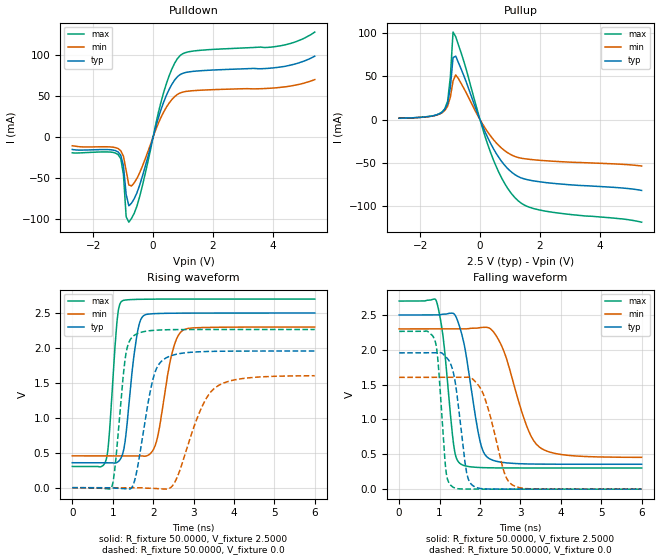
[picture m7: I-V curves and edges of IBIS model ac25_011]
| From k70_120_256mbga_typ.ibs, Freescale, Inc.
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|   Model ac25_011
[Model]  ac25_011
Model_type Output
Polarity   Non-Inverting
Enable   Active-High
Vmeas =  1.2500V
Cref =   5.0000pF
Rref =   50.0000
C_comp   2.8000pF   2.5000pF   3.3000pF
[Temperature Range]   25.0000   0.1250k   -40.0000
[Voltage Range]   2.5000V   2.3000V   2.7000V
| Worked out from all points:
|   slope of the pulldown table from 0 to 0.375 V, typ, clamps not added: 8.44 ohm
|   slope of the pullup table from 0 to 0.375 V, typ, clamps not added: 13 ohm
|   rising waveform, R_fixture 50.0000, V_fixture 2.5000: 20-80 % time 237ps typ, 326ps min, 165ps max; typ from 0.357 V to 2.5 V
|   rising waveform, R_fixture 50.0000, V_fixture 0.0: 20-80 % time 357ps typ, 618ps min, 215ps max; typ from 0 V to 1.96 V
|   falling waveform, R_fixture 50.0000, V_fixture 2.5000: 20-80 % time 355ps typ, 590ps min, 239ps max; typ from 2.5 V to 0.357 V
|   falling waveform, R_fixture 50.0000, V_fixture 0.0: 20-80 % time 250ps typ, 427ps min, 163ps max; typ from 1.96 V to 0 V
[Pulldown]
|Voltage   I(typ)   I(min)   I(max)
-2.7V     -15.15mA   -10.66mA   -19.23mA
-1.17V    -18.15mA   -14.03mA   -21.31mA
-1.08V    -22.21mA   -16.65mA   -26.35mA
-990mV    -35.19mA   -23.45mA   -45.8mA
-900mV    -69.89mA   -40.79mA   -97.1mA
-810mV    -83.68mA   -58.36mA   -103.6mA
-450mV    -58.66mA   -43.64mA   -72.6mA
360mV     43.1mA     30.89mA    55.11mA
630mV     64.28mA    45.66mA    82.94mA
900mV     75.87mA    53.52mA    98.99mA
4.23V     85.03mA    60.3mA     110.8mA
5.4V      98.3mA     69.8mA     127.6mA
[Pullup]
|Voltage   I(typ)   I(min)   I(max)
-2.7V     1.5mA      1.5mA      1.5mA
-1.17V    11.9mA     10.58mA    12.73mA
-1.08V    18.75mA    15.51mA    21.24mA
-990mV    36.75mA    25.9mA     48.78mA
-900mV    71.45mA    44.56mA    100.8mA
-810mV    73.08mA    51.48mA    95.46mA
-720mV    65.66mA    47.17mA    86.05mA
360mV     -27.87mA   -19.2mA    -38.53mA
720mV     -48.12mA   -32.86mA   -67.1mA
1.17V     -63.57mA   -42.6mA    -90.11mA
2.16V     -72.48mA   -47.39mA   -105.4mA
5.4V      -81.68mA   -53.55mA   -118.3mA
[Ramp]
| variable   typ   min   max
dV/dt_r  1.1737/0.3567n   0.9617/0.6175n   1.3589/0.2153n
dV/dt_f  1.2856/0.3546n   1.1061/0.5897n   1.4377/0.2388n
R_load = 50.0000
[Rising Waveform]
R_fixture= 50.0000
V_fixture= 2.5000
V_fixture_min= 2.3000
V_fixture_max= 2.7000
|time   V(typ)   V(min)   V(max)
0s        357.4mV    455.5mV    303.8mV
832.9ps   357.4mV    455.5mV    390.9mV
1.113ns   363.8mV    455.5mV    2.416V
1.225ns   448.8mV    455.5mV    2.67V
1.582ns   2.119V     455.5mV    2.696V
1.758ns   2.459V     452.2mV    2.698V
2.066ns   2.492V     627.4mV    2.699V
2.434ns   2.497V     1.841V     2.7V
2.706ns   2.499V     2.24V      2.7V
6ns       2.5V       2.3V       2.7V
[Rising Waveform]
R_fixture= 50.0000
V_fixture= 0.0
|time   V(typ)   V(min)   V(max)
0s        2.817nV    276.3nV    859.2pV
975.6ps   376.2uV    286.5nV    8.971mV
1.068ns   -7.425mV   262nV      350.9mV
1.315ns   -17.38mV   506.8nV    1.872V
1.561ns   143mV      -11.37uV   2.191V
1.987ns   1.532V     -8.683mV   2.251V
2.277ns   1.843V     -19.25mV   2.26V
2.566ns   1.909V     111.1mV    2.263V
3.512ns   1.952V     1.42V      2.265V
6ns       1.956V     1.603V     2.265V
[Falling Waveform]
R_fixture= 50.0000
V_fixture= 2.5000
V_fixture_min= 2.3000
V_fixture_max= 2.7000
|time   V(typ)   V(min)   V(max)
0s        2.5V       2.3V       2.7V
920.6ps   2.5V       2.3V       2.7V
1.098ns   2.512V     2.3V       2.135V
1.365ns   2.512V     2.3V       571.5mV
1.526ns   2.276V     2.3V       360mV
1.976ns   756.4mV    2.316V     311.1mV
2.201ns   449.7mV    2.319V     306.8mV
2.546ns   385mV      2.045V     304.6mV
3.466ns   359.5mV    605.9mV    303.8mV
6ns       357.4mV    456.5mV    303.8mV
[Falling Waveform]
R_fixture= 50.0000
V_fixture= 0.0
|time   V(typ)   V(min)   V(max)
0s        1.956V     1.605V     2.265V
883.8ps   1.956V     1.605V     2.137V
967.4ps   1.957V     1.605V     1.798V
1.154ns   1.901V     1.605V     287mV
1.317ns   1.727V     1.605V     35.06mV
1.658ns   275.8mV    1.605V     1.731mV
1.838ns   45.16mV    1.571V     876.8uV
2.1ns     4.613mV    1.339V     320.8uV
2.79ns    482.6uV    65.91mV    23.4uV
6ns       84.45nV    14.95uV    -177.7nV
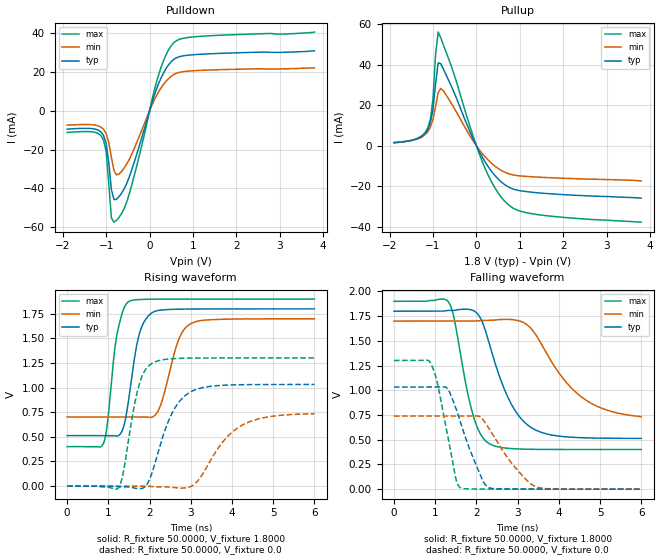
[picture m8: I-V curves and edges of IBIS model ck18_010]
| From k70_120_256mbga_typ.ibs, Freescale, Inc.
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|   Model ck18_010
[Model]  ck18_010
Model_type Output
Polarity   Non-Inverting
Enable   Active-High
Vmeas =  0.9000V
Cref =   5.0000pF
Rref =   50.0000
C_comp   2.8000pF   2.5000pF   3.3000pF
[Temperature Range]   25.0000   0.1250k   -40.0000
[Voltage Range]   1.8000V   1.7000V   1.9000V
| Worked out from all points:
|   slope of the pulldown table from 0 to 0.27 V, typ, clamps not added: 15.7 ohm
|   slope of the pullup table from 0 to 0.27 V, typ, clamps not added: 26.3 ohm
|   rising waveform, R_fixture 50.0000, V_fixture 1.8000: 20-80 % time 296ps typ, 389ps min, 244ps max; typ from 0.513 V to 1.8 V
|   rising waveform, R_fixture 50.0000, V_fixture 0.0: 20-80 % time 552ps typ, 806ps min, 342ps max; typ from 0 V to 1.03 V
|   falling waveform, R_fixture 50.0000, V_fixture 1.8000: 20-80 % time 714ps typ, 1.05ns min, 437ps max; typ from 1.8 V to 0.514 V
|   falling waveform, R_fixture 50.0000, V_fixture 0.0: 20-80 % time 535ps typ, 755ps min, 360ps max; typ from 1.03 V to 0 V
[Pulldown]
|Voltage   I(typ)   I(min)   I(max)
-1.9V     -9.455mA   -7.373mA   -11.21mA
-1.3V     -9.27mA    -7.246mA   -10.93mA
-1.06V    -12.74mA   -9.549mA   -15.16mA
-1V       -16.97mA   -11.81mA   -21.28mA
-880mV    -40.74mA   -24.12mA   -55.33mA
-820mV    -45.94mA   -31mA      -57.57mA
-700mV    -44.25mA   -32.6mA    -54.97mA
-520mV    -37.17mA   -27.26mA   -46.71mA
200mV     13.59mA    9.514mA    17.97mA
380mV     21.87mA    15.33mA    28.97mA
560mV     26.62mA    18.78mA    35.25mA
3.8V      31mA       22.2mA     40.7mA
[Pullup]
|Voltage   I(typ)   I(min)   I(max)
-1.9V     1.5mA      1.5mA      1.5mA
-1.36V    3.5mA      3.29mA     3.6mA
-1.12V    7.95mA     6.86mA     8.75mA
-1.06V    11.25mA    9.12mA     13.03mA
-1V       17.82mA    12.94mA    22.96mA
-940mV    30.55mA    19.28mA    45.07mA
-880mV    40.83mA    26.15mA    55.99mA
-760mV    37.76mA    27.03mA    49.63mA
140mV     -5.747mA   -3.95mA    -8.08mA
680mV     -19.58mA   -13.32mA   -27.96mA
1.4V      -23.19mA   -15.47mA   -33.93mA
3.8V      -25.86mA   -17.36mA   -37.71mA
[Ramp]
| variable   typ   min   max
dV/dt_r  0.6195/0.5521n   0.4411/0.8058n   0.7810/0.3420n
dV/dt_f  0.7718/0.7144n   0.5801/1.0470n   0.8992/0.4372n
R_load = 50.0000
[Rising Waveform]
R_fixture= 50.0000
V_fixture= 1.8000
V_fixture_min= 1.7000
V_fixture_max= 1.9000
|time   V(typ)   V(min)   V(max)
0s        513.2mV    702.3mV    401.3mV
884.6ps   513.2mV    702.3mV    437mV
1.202ns   508.5mV    702.3mV    1.522V
1.364ns   593.7mV    702.3mV    1.791V
1.499ns   896.4mV    702.3mV    1.875V
1.761ns   1.559V     702.5mV    1.895V
2.087ns   1.768V     705.1mV    1.899V
2.711ns   1.797V     1.494V     1.9V
2.96ns    1.799V     1.64V      1.9V
6ns       1.8V       1.7V       1.9V
[Rising Waveform]
R_fixture= 50.0000
V_fixture= 0.0
|time   V(typ)   V(min)   V(max)
0s        3.82nV     410nV      1.002nV
1.251ns   -6.64mV    766.3nV    -14.2mV
1.355ns   -7.129mV   650.3nV    121.8mV
1.736ns   -25.97mV   13.67uV    1.014V
1.926ns   11.16mV    236uV      1.198V
2.074ns   153.3mV    -5.793mV   1.25V
2.523ns   721.6mV    -11.3mV    1.294V
2.996ns   957.3mV    -4.407mV   1.3V
4.204ns   1.03V      608.5mV    1.302V
6ns       1.033V     735.2mV    1.302V
[Falling Waveform]
R_fixture= 50.0000
V_fixture= 1.8000
V_fixture_min= 1.7000
V_fixture_max= 1.9000
|time   V(typ)   V(min)   V(max)
0s        1.8V       1.7V       1.9V
1.334ns   1.808V     1.7V       1.887V
1.454ns   1.808V     1.7V       1.742V
1.917ns   1.808V     1.7V       754.8mV
2.13ns    1.703V     1.706V     536.5mV
2.332ns   1.445V     1.707V     455.4mV
2.826ns   877.7mV    1.716V     411.1mV
3.324ns   624.8mV    1.626V     403.3mV
4.502ns   521.4mV    948.4mV    401.4mV
6ns       513.6mV    733.2mV    401.3mV
[Falling Waveform]
R_fixture= 50.0000
V_fixture= 0.0
|time   V(typ)   V(min)   V(max)
0s        1.033V     739.4mV    1.302V
896.5ps   1.033V     739.4mV    1.27V
1.047ns   1.032V     739.4mV    1.088V
1.292ns   1.02V      739.4mV    567.2mV
1.496ns   826.6mV    739.4mV    117.4mV
1.619ns   671mV      739.4mV    12.69mV
2.077ns   160.5mV    734.8mV    1.113mV
2.319ns   13.65mV    604.4mV    491.8uV
3.447ns   322.6uV    24.79mV    14.68uV
6ns       1.829uV    73.99uV    149.7nV
